# Generated by FakeRAM 2.0
VERSION 5.7 ;
BUSBITCHARS "[]" ;
PROPERTYDEFINITIONS
  MACRO width INTEGER ;
  MACRO depth INTEGER ;
  MACRO banks INTEGER ;
END PROPERTYDEFINITIONS
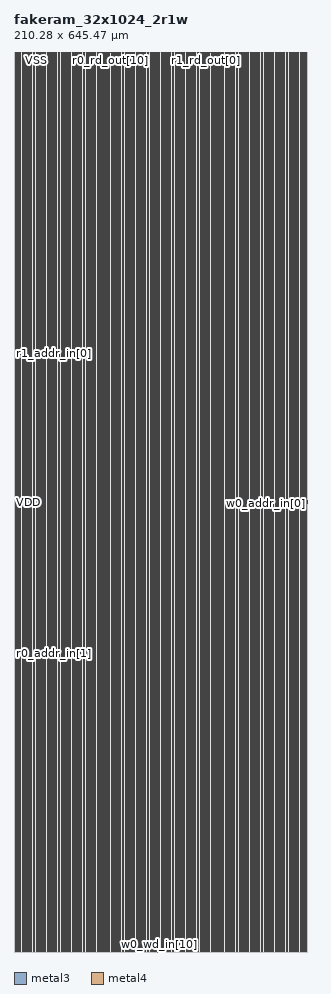
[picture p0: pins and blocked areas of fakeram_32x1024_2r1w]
MACRO fakeram_32x1024_2r1w
  PROPERTY width 32 ;
  PROPERTY depth 1024 ;
  PROPERTY banks 1 ;
  FOREIGN fakeram_32x1024_2r1w 0 0 ;
  SYMMETRY X Y R90 ;
  SIZE 210.280 BY 645.470 ;
  CLASS BLOCK ;
  PIN r0_addr_in[0]
    DIRECTION INPUT ;
    USE SIGNAL ;
    SHAPE ABUTMENT ;
    PORT
      LAYER metal3 ;
      RECT 0.000 214.200 0.070 214.270 ;
    END
  END r0_addr_in[0]
  PIN r0_addr_in[1]
    DIRECTION INPUT ;
    USE SIGNAL ;
    SHAPE ABUTMENT ;
    PORT
      LAYER metal3 ;
      RECT 0.000 214.340 0.070 214.410 ;
    END
  END r0_addr_in[1]
  PIN r0_addr_in[2]
    DIRECTION INPUT ;
    USE SIGNAL ;
    SHAPE ABUTMENT ;
    PORT
      LAYER metal3 ;
      RECT 0.000 214.480 0.070 214.550 ;
    END
  END r0_addr_in[2]
  PIN r0_addr_in[3]
    DIRECTION INPUT ;
    USE SIGNAL ;
    SHAPE ABUTMENT ;
    PORT
      LAYER metal3 ;
      RECT 0.000 214.620 0.070 214.690 ;
    END
  END r0_addr_in[3]
  PIN r0_addr_in[4]
    DIRECTION INPUT ;
    USE SIGNAL ;
    SHAPE ABUTMENT ;
    PORT
      LAYER metal3 ;
      RECT 0.000 214.760 0.070 214.830 ;
    END
  END r0_addr_in[4]
  PIN r0_addr_in[5]
    DIRECTION INPUT ;
    USE SIGNAL ;
    SHAPE ABUTMENT ;
    PORT
      LAYER metal3 ;
      RECT 0.000 214.900 0.070 214.970 ;
    END
  END r0_addr_in[5]
  PIN r0_addr_in[6]
    DIRECTION INPUT ;
    USE SIGNAL ;
    SHAPE ABUTMENT ;
    PORT
      LAYER metal3 ;
      RECT 0.000 215.040 0.070 215.110 ;
    END
  END r0_addr_in[6]
  PIN r0_addr_in[7]
    DIRECTION INPUT ;
    USE SIGNAL ;
    SHAPE ABUTMENT ;
    PORT
      LAYER metal3 ;
      RECT 0.000 215.180 0.070 215.250 ;
    END
  END r0_addr_in[7]
  PIN r0_addr_in[8]
    DIRECTION INPUT ;
    USE SIGNAL ;
    SHAPE ABUTMENT ;
    PORT
      LAYER metal3 ;
      RECT 0.000 215.320 0.070 215.390 ;
    END
  END r0_addr_in[8]
  PIN r0_addr_in[9]
    DIRECTION INPUT ;
    USE SIGNAL ;
    SHAPE ABUTMENT ;
    PORT
      LAYER metal3 ;
      RECT 0.000 215.460 0.070 215.530 ;
    END
  END r0_addr_in[9]
  PIN r0_ce_in
    DIRECTION INPUT ;
    USE SIGNAL ;
    SHAPE ABUTMENT ;
    PORT
      LAYER metal3 ;
      RECT 0.000 215.740 0.070 215.810 ;
    END
  END r0_ce_in
  PIN r0_clk
    DIRECTION INPUT ;
    USE SIGNAL ;
    SHAPE ABUTMENT ;
    PORT
      LAYER metal3 ;
      RECT 0.000 215.880 0.070 215.950 ;
    END
  END r0_clk
  PIN r0_rd_out[0]
    DIRECTION OUTPUT ;
    USE SIGNAL ;
    SHAPE ABUTMENT ;
    PORT
      LAYER metal3 ;
      RECT 67.725 645.400 67.795 645.470 ;
    END
  END r0_rd_out[0]
  PIN r0_rd_out[1]
    DIRECTION OUTPUT ;
    USE SIGNAL ;
    SHAPE ABUTMENT ;
    PORT
      LAYER metal3 ;
      RECT 67.865 645.400 67.935 645.470 ;
    END
  END r0_rd_out[1]
  PIN r0_rd_out[2]
    DIRECTION OUTPUT ;
    USE SIGNAL ;
    SHAPE ABUTMENT ;
    PORT
      LAYER metal3 ;
      RECT 68.005 645.400 68.075 645.470 ;
    END
  END r0_rd_out[2]
  PIN r0_rd_out[3]
    DIRECTION OUTPUT ;
    USE SIGNAL ;
    SHAPE ABUTMENT ;
    PORT
      LAYER metal3 ;
      RECT 68.145 645.400 68.215 645.470 ;
    END
  END r0_rd_out[3]
  PIN r0_rd_out[4]
    DIRECTION OUTPUT ;
    USE SIGNAL ;
    SHAPE ABUTMENT ;
    PORT
      LAYER metal3 ;
      RECT 68.285 645.400 68.355 645.470 ;
    END
  END r0_rd_out[4]
  PIN r0_rd_out[5]
    DIRECTION OUTPUT ;
    USE SIGNAL ;
    SHAPE ABUTMENT ;
    PORT
      LAYER metal3 ;
      RECT 68.425 645.400 68.495 645.470 ;
    END
  END r0_rd_out[5]
  PIN r0_rd_out[6]
    DIRECTION OUTPUT ;
    USE SIGNAL ;
    SHAPE ABUTMENT ;
    PORT
      LAYER metal3 ;
      RECT 68.565 645.400 68.635 645.470 ;
    END
  END r0_rd_out[6]
  PIN r0_rd_out[7]
    DIRECTION OUTPUT ;
    USE SIGNAL ;
    SHAPE ABUTMENT ;
    PORT
      LAYER metal3 ;
      RECT 68.705 645.400 68.775 645.470 ;
    END
  END r0_rd_out[7]
  PIN r0_rd_out[8]
    DIRECTION OUTPUT ;
    USE SIGNAL ;
    SHAPE ABUTMENT ;
    PORT
      LAYER metal3 ;
      RECT 68.845 645.400 68.915 645.470 ;
    END
  END r0_rd_out[8]
  PIN r0_rd_out[9]
    DIRECTION OUTPUT ;
    USE SIGNAL ;
    SHAPE ABUTMENT ;
    PORT
      LAYER metal3 ;
      RECT 68.985 645.400 69.055 645.470 ;
    END
  END r0_rd_out[9]
  PIN r0_rd_out[10]
    DIRECTION OUTPUT ;
    USE SIGNAL ;
    SHAPE ABUTMENT ;
    PORT
      LAYER metal3 ;
      RECT 69.125 645.400 69.195 645.470 ;
    END
  END r0_rd_out[10]
  PIN r0_rd_out[11]
    DIRECTION OUTPUT ;
    USE SIGNAL ;
    SHAPE ABUTMENT ;
    PORT
      LAYER metal3 ;
      RECT 69.265 645.400 69.335 645.470 ;
    END
  END r0_rd_out[11]
  PIN r0_rd_out[12]
    DIRECTION OUTPUT ;
    USE SIGNAL ;
    SHAPE ABUTMENT ;
    PORT
      LAYER metal3 ;
      RECT 69.405 645.400 69.475 645.470 ;
    END
  END r0_rd_out[12]
  PIN r0_rd_out[13]
    DIRECTION OUTPUT ;
    USE SIGNAL ;
    SHAPE ABUTMENT ;
    PORT
      LAYER metal3 ;
      RECT 69.545 645.400 69.615 645.470 ;
    END
  END r0_rd_out[13]
  PIN r0_rd_out[14]
    DIRECTION OUTPUT ;
    USE SIGNAL ;
    SHAPE ABUTMENT ;
    PORT
      LAYER metal3 ;
      RECT 69.685 645.400 69.755 645.470 ;
    END
  END r0_rd_out[14]
  PIN r0_rd_out[15]
    DIRECTION OUTPUT ;
    USE SIGNAL ;
    SHAPE ABUTMENT ;
    PORT
      LAYER metal3 ;
      RECT 69.825 645.400 69.895 645.470 ;
    END
  END r0_rd_out[15]
  PIN r0_rd_out[16]
    DIRECTION OUTPUT ;
    USE SIGNAL ;
    SHAPE ABUTMENT ;
    PORT
      LAYER metal3 ;
      RECT 69.965 645.400 70.035 645.470 ;
    END
  END r0_rd_out[16]
  PIN r0_rd_out[17]
    DIRECTION OUTPUT ;
    USE SIGNAL ;
    SHAPE ABUTMENT ;
    PORT
      LAYER metal3 ;
      RECT 70.105 645.400 70.175 645.470 ;
    END
  END r0_rd_out[17]
  PIN r0_rd_out[18]
    DIRECTION OUTPUT ;
    USE SIGNAL ;
    SHAPE ABUTMENT ;
    PORT
      LAYER metal3 ;
      RECT 70.245 645.400 70.315 645.470 ;
    END
  END r0_rd_out[18]
  PIN r0_rd_out[19]
    DIRECTION OUTPUT ;
    USE SIGNAL ;
    SHAPE ABUTMENT ;
    PORT
      LAYER metal3 ;
      RECT 70.385 645.400 70.455 645.470 ;
    END
  END r0_rd_out[19]
  PIN r0_rd_out[20]
    DIRECTION OUTPUT ;
    USE SIGNAL ;
    SHAPE ABUTMENT ;
    PORT
      LAYER metal3 ;
      RECT 70.525 645.400 70.595 645.470 ;
    END
  END r0_rd_out[20]
  PIN r0_rd_out[21]
    DIRECTION OUTPUT ;
    USE SIGNAL ;
    SHAPE ABUTMENT ;
    PORT
      LAYER metal3 ;
      RECT 70.665 645.400 70.735 645.470 ;
    END
  END r0_rd_out[21]
  PIN r0_rd_out[22]
    DIRECTION OUTPUT ;
    USE SIGNAL ;
    SHAPE ABUTMENT ;
    PORT
      LAYER metal3 ;
      RECT 70.805 645.400 70.875 645.470 ;
    END
  END r0_rd_out[22]
  PIN r0_rd_out[23]
    DIRECTION OUTPUT ;
    USE SIGNAL ;
    SHAPE ABUTMENT ;
    PORT
      LAYER metal3 ;
      RECT 70.945 645.400 71.015 645.470 ;
    END
  END r0_rd_out[23]
  PIN r0_rd_out[24]
    DIRECTION OUTPUT ;
    USE SIGNAL ;
    SHAPE ABUTMENT ;
    PORT
      LAYER metal3 ;
      RECT 71.085 645.400 71.155 645.470 ;
    END
  END r0_rd_out[24]
  PIN r0_rd_out[25]
    DIRECTION OUTPUT ;
    USE SIGNAL ;
    SHAPE ABUTMENT ;
    PORT
      LAYER metal3 ;
      RECT 71.225 645.400 71.295 645.470 ;
    END
  END r0_rd_out[25]
  PIN r0_rd_out[26]
    DIRECTION OUTPUT ;
    USE SIGNAL ;
    SHAPE ABUTMENT ;
    PORT
      LAYER metal3 ;
      RECT 71.365 645.400 71.435 645.470 ;
    END
  END r0_rd_out[26]
  PIN r0_rd_out[27]
    DIRECTION OUTPUT ;
    USE SIGNAL ;
    SHAPE ABUTMENT ;
    PORT
      LAYER metal3 ;
      RECT 71.505 645.400 71.575 645.470 ;
    END
  END r0_rd_out[27]
  PIN r0_rd_out[28]
    DIRECTION OUTPUT ;
    USE SIGNAL ;
    SHAPE ABUTMENT ;
    PORT
      LAYER metal3 ;
      RECT 71.645 645.400 71.715 645.470 ;
    END
  END r0_rd_out[28]
  PIN r0_rd_out[29]
    DIRECTION OUTPUT ;
    USE SIGNAL ;
    SHAPE ABUTMENT ;
    PORT
      LAYER metal3 ;
      RECT 71.785 645.400 71.855 645.470 ;
    END
  END r0_rd_out[29]
  PIN r0_rd_out[30]
    DIRECTION OUTPUT ;
    USE SIGNAL ;
    SHAPE ABUTMENT ;
    PORT
      LAYER metal3 ;
      RECT 71.925 645.400 71.995 645.470 ;
    END
  END r0_rd_out[30]
  PIN r0_rd_out[31]
    DIRECTION OUTPUT ;
    USE SIGNAL ;
    SHAPE ABUTMENT ;
    PORT
      LAYER metal3 ;
      RECT 72.065 645.400 72.135 645.470 ;
    END
  END r0_rd_out[31]
  PIN r1_addr_in[0]
    DIRECTION INPUT ;
    USE SIGNAL ;
    SHAPE ABUTMENT ;
    PORT
      LAYER metal3 ;
      RECT 0.000 429.240 0.070 429.310 ;
    END
  END r1_addr_in[0]
  PIN r1_addr_in[1]
    DIRECTION INPUT ;
    USE SIGNAL ;
    SHAPE ABUTMENT ;
    PORT
      LAYER metal3 ;
      RECT 0.000 429.380 0.070 429.450 ;
    END
  END r1_addr_in[1]
  PIN r1_addr_in[2]
    DIRECTION INPUT ;
    USE SIGNAL ;
    SHAPE ABUTMENT ;
    PORT
      LAYER metal3 ;
      RECT 0.000 429.520 0.070 429.590 ;
    END
  END r1_addr_in[2]
  PIN r1_addr_in[3]
    DIRECTION INPUT ;
    USE SIGNAL ;
    SHAPE ABUTMENT ;
    PORT
      LAYER metal3 ;
      RECT 0.000 429.660 0.070 429.730 ;
    END
  END r1_addr_in[3]
  PIN r1_addr_in[4]
    DIRECTION INPUT ;
    USE SIGNAL ;
    SHAPE ABUTMENT ;
    PORT
      LAYER metal3 ;
      RECT 0.000 429.800 0.070 429.870 ;
    END
  END r1_addr_in[4]
  PIN r1_addr_in[5]
    DIRECTION INPUT ;
    USE SIGNAL ;
    SHAPE ABUTMENT ;
    PORT
      LAYER metal3 ;
      RECT 0.000 429.940 0.070 430.010 ;
    END
  END r1_addr_in[5]
  PIN r1_addr_in[6]
    DIRECTION INPUT ;
    USE SIGNAL ;
    SHAPE ABUTMENT ;
    PORT
      LAYER metal3 ;
      RECT 0.000 430.080 0.070 430.150 ;
    END
  END r1_addr_in[6]
  PIN r1_addr_in[7]
    DIRECTION INPUT ;
    USE SIGNAL ;
    SHAPE ABUTMENT ;
    PORT
      LAYER metal3 ;
      RECT 0.000 430.220 0.070 430.290 ;
    END
  END r1_addr_in[7]
  PIN r1_addr_in[8]
    DIRECTION INPUT ;
    USE SIGNAL ;
    SHAPE ABUTMENT ;
    PORT
      LAYER metal3 ;
      RECT 0.000 430.360 0.070 430.430 ;
    END
  END r1_addr_in[8]
  PIN r1_addr_in[9]
    DIRECTION INPUT ;
    USE SIGNAL ;
    SHAPE ABUTMENT ;
    PORT
      LAYER metal3 ;
      RECT 0.000 430.500 0.070 430.570 ;
    END
  END r1_addr_in[9]
  PIN r1_ce_in
    DIRECTION INPUT ;
    USE SIGNAL ;
    SHAPE ABUTMENT ;
    PORT
      LAYER metal3 ;
      RECT 0.000 430.780 0.070 430.850 ;
    END
  END r1_ce_in
  PIN r1_clk
    DIRECTION INPUT ;
    USE SIGNAL ;
    SHAPE ABUTMENT ;
    PORT
      LAYER metal3 ;
      RECT 0.000 430.920 0.070 430.990 ;
    END
  END r1_clk
  PIN r1_rd_out[0]
    DIRECTION OUTPUT ;
    USE SIGNAL ;
    SHAPE ABUTMENT ;
    PORT
      LAYER metal3 ;
      RECT 137.725 645.400 137.795 645.470 ;
    END
  END r1_rd_out[0]
  PIN r1_rd_out[1]
    DIRECTION OUTPUT ;
    USE SIGNAL ;
    SHAPE ABUTMENT ;
    PORT
      LAYER metal3 ;
      RECT 137.865 645.400 137.935 645.470 ;
    END
  END r1_rd_out[1]
  PIN r1_rd_out[2]
    DIRECTION OUTPUT ;
    USE SIGNAL ;
    SHAPE ABUTMENT ;
    PORT
      LAYER metal3 ;
      RECT 138.005 645.400 138.075 645.470 ;
    END
  END r1_rd_out[2]
  PIN r1_rd_out[3]
    DIRECTION OUTPUT ;
    USE SIGNAL ;
    SHAPE ABUTMENT ;
    PORT
      LAYER metal3 ;
      RECT 138.145 645.400 138.215 645.470 ;
    END
  END r1_rd_out[3]
  PIN r1_rd_out[4]
    DIRECTION OUTPUT ;
    USE SIGNAL ;
    SHAPE ABUTMENT ;
    PORT
      LAYER metal3 ;
      RECT 138.285 645.400 138.355 645.470 ;
    END
  END r1_rd_out[4]
  PIN r1_rd_out[5]
    DIRECTION OUTPUT ;
    USE SIGNAL ;
    SHAPE ABUTMENT ;
    PORT
      LAYER metal3 ;
      RECT 138.425 645.400 138.495 645.470 ;
    END
  END r1_rd_out[5]
  PIN r1_rd_out[6]
    DIRECTION OUTPUT ;
    USE SIGNAL ;
    SHAPE ABUTMENT ;
    PORT
      LAYER metal3 ;
      RECT 138.565 645.400 138.635 645.470 ;
    END
  END r1_rd_out[6]
  PIN r1_rd_out[7]
    DIRECTION OUTPUT ;
    USE SIGNAL ;
    SHAPE ABUTMENT ;
    PORT
      LAYER metal3 ;
      RECT 138.705 645.400 138.775 645.470 ;
    END
  END r1_rd_out[7]
  PIN r1_rd_out[8]
    DIRECTION OUTPUT ;
    USE SIGNAL ;
    SHAPE ABUTMENT ;
    PORT
      LAYER metal3 ;
      RECT 138.845 645.400 138.915 645.470 ;
    END
  END r1_rd_out[8]
  PIN r1_rd_out[9]
    DIRECTION OUTPUT ;
    USE SIGNAL ;
    SHAPE ABUTMENT ;
    PORT
      LAYER metal3 ;
      RECT 138.985 645.400 139.055 645.470 ;
    END
  END r1_rd_out[9]
  PIN r1_rd_out[10]
    DIRECTION OUTPUT ;
    USE SIGNAL ;
    SHAPE ABUTMENT ;
    PORT
      LAYER metal3 ;
      RECT 139.125 645.400 139.195 645.470 ;
    END
  END r1_rd_out[10]
  PIN r1_rd_out[11]
    DIRECTION OUTPUT ;
    USE SIGNAL ;
    SHAPE ABUTMENT ;
    PORT
      LAYER metal3 ;
      RECT 139.265 645.400 139.335 645.470 ;
    END
  END r1_rd_out[11]
  PIN r1_rd_out[12]
    DIRECTION OUTPUT ;
    USE SIGNAL ;
    SHAPE ABUTMENT ;
    PORT
      LAYER metal3 ;
      RECT 139.405 645.400 139.475 645.470 ;
    END
  END r1_rd_out[12]
  PIN r1_rd_out[13]
    DIRECTION OUTPUT ;
    USE SIGNAL ;
    SHAPE ABUTMENT ;
    PORT
      LAYER metal3 ;
      RECT 139.545 645.400 139.615 645.470 ;
    END
  END r1_rd_out[13]
  PIN r1_rd_out[14]
    DIRECTION OUTPUT ;
    USE SIGNAL ;
    SHAPE ABUTMENT ;
    PORT
      LAYER metal3 ;
      RECT 139.685 645.400 139.755 645.470 ;
    END
  END r1_rd_out[14]
  PIN r1_rd_out[15]
    DIRECTION OUTPUT ;
    USE SIGNAL ;
    SHAPE ABUTMENT ;
    PORT
      LAYER metal3 ;
      RECT 139.825 645.400 139.895 645.470 ;
    END
  END r1_rd_out[15]
  PIN r1_rd_out[16]
    DIRECTION OUTPUT ;
    USE SIGNAL ;
    SHAPE ABUTMENT ;
    PORT
      LAYER metal3 ;
      RECT 139.965 645.400 140.035 645.470 ;
    END
  END r1_rd_out[16]
  PIN r1_rd_out[17]
    DIRECTION OUTPUT ;
    USE SIGNAL ;
    SHAPE ABUTMENT ;
    PORT
      LAYER metal3 ;
      RECT 140.105 645.400 140.175 645.470 ;
    END
  END r1_rd_out[17]
  PIN r1_rd_out[18]
    DIRECTION OUTPUT ;
    USE SIGNAL ;
    SHAPE ABUTMENT ;
    PORT
      LAYER metal3 ;
      RECT 140.245 645.400 140.315 645.470 ;
    END
  END r1_rd_out[18]
  PIN r1_rd_out[19]
    DIRECTION OUTPUT ;
    USE SIGNAL ;
    SHAPE ABUTMENT ;
    PORT
      LAYER metal3 ;
      RECT 140.385 645.400 140.455 645.470 ;
    END
  END r1_rd_out[19]
  PIN r1_rd_out[20]
    DIRECTION OUTPUT ;
    USE SIGNAL ;
    SHAPE ABUTMENT ;
    PORT
      LAYER metal3 ;
      RECT 140.525 645.400 140.595 645.470 ;
    END
  END r1_rd_out[20]
  PIN r1_rd_out[21]
    DIRECTION OUTPUT ;
    USE SIGNAL ;
    SHAPE ABUTMENT ;
    PORT
      LAYER metal3 ;
      RECT 140.665 645.400 140.735 645.470 ;
    END
  END r1_rd_out[21]
  PIN r1_rd_out[22]
    DIRECTION OUTPUT ;
    USE SIGNAL ;
    SHAPE ABUTMENT ;
    PORT
      LAYER metal3 ;
      RECT 140.805 645.400 140.875 645.470 ;
    END
  END r1_rd_out[22]
  PIN r1_rd_out[23]
    DIRECTION OUTPUT ;
    USE SIGNAL ;
    SHAPE ABUTMENT ;
    PORT
      LAYER metal3 ;
      RECT 140.945 645.400 141.015 645.470 ;
    END
  END r1_rd_out[23]
  PIN r1_rd_out[24]
    DIRECTION OUTPUT ;
    USE SIGNAL ;
    SHAPE ABUTMENT ;
    PORT
      LAYER metal3 ;
      RECT 141.085 645.400 141.155 645.470 ;
    END
  END r1_rd_out[24]
  PIN r1_rd_out[25]
    DIRECTION OUTPUT ;
    USE SIGNAL ;
    SHAPE ABUTMENT ;
    PORT
      LAYER metal3 ;
      RECT 141.225 645.400 141.295 645.470 ;
    END
  END r1_rd_out[25]
  PIN r1_rd_out[26]
    DIRECTION OUTPUT ;
    USE SIGNAL ;
    SHAPE ABUTMENT ;
    PORT
      LAYER metal3 ;
      RECT 141.365 645.400 141.435 645.470 ;
    END
  END r1_rd_out[26]
  PIN r1_rd_out[27]
    DIRECTION OUTPUT ;
    USE SIGNAL ;
    SHAPE ABUTMENT ;
    PORT
      LAYER metal3 ;
      RECT 141.505 645.400 141.575 645.470 ;
    END
  END r1_rd_out[27]
  PIN r1_rd_out[28]
    DIRECTION OUTPUT ;
    USE SIGNAL ;
    SHAPE ABUTMENT ;
    PORT
      LAYER metal3 ;
      RECT 141.645 645.400 141.715 645.470 ;
    END
  END r1_rd_out[28]
  PIN r1_rd_out[29]
    DIRECTION OUTPUT ;
    USE SIGNAL ;
    SHAPE ABUTMENT ;
    PORT
      LAYER metal3 ;
      RECT 141.785 645.400 141.855 645.470 ;
    END
  END r1_rd_out[29]
  PIN r1_rd_out[30]
    DIRECTION OUTPUT ;
    USE SIGNAL ;
    SHAPE ABUTMENT ;
    PORT
      LAYER metal3 ;
      RECT 141.925 645.400 141.995 645.470 ;
    END
  END r1_rd_out[30]
  PIN r1_rd_out[31]
    DIRECTION OUTPUT ;
    USE SIGNAL ;
    SHAPE ABUTMENT ;
    PORT
      LAYER metal3 ;
      RECT 142.065 645.400 142.135 645.470 ;
    END
  END r1_rd_out[31]
  PIN w0_addr_in[0]
    DIRECTION INPUT ;
    USE SIGNAL ;
    SHAPE ABUTMENT ;
    PORT
      LAYER metal3 ;
      RECT 210.210 321.720 210.280 321.790 ;
    END
  END w0_addr_in[0]
  PIN w0_addr_in[1]
    DIRECTION INPUT ;
    USE SIGNAL ;
    SHAPE ABUTMENT ;
    PORT
      LAYER metal3 ;
      RECT 210.210 321.860 210.280 321.930 ;
    END
  END w0_addr_in[1]
  PIN w0_addr_in[2]
    DIRECTION INPUT ;
    USE SIGNAL ;
    SHAPE ABUTMENT ;
    PORT
      LAYER metal3 ;
      RECT 210.210 322.000 210.280 322.070 ;
    END
  END w0_addr_in[2]
  PIN w0_addr_in[3]
    DIRECTION INPUT ;
    USE SIGNAL ;
    SHAPE ABUTMENT ;
    PORT
      LAYER metal3 ;
      RECT 210.210 322.140 210.280 322.210 ;
    END
  END w0_addr_in[3]
  PIN w0_addr_in[4]
    DIRECTION INPUT ;
    USE SIGNAL ;
    SHAPE ABUTMENT ;
    PORT
      LAYER metal3 ;
      RECT 210.210 322.280 210.280 322.350 ;
    END
  END w0_addr_in[4]
  PIN w0_addr_in[5]
    DIRECTION INPUT ;
    USE SIGNAL ;
    SHAPE ABUTMENT ;
    PORT
      LAYER metal3 ;
      RECT 210.210 322.420 210.280 322.490 ;
    END
  END w0_addr_in[5]
  PIN w0_addr_in[6]
    DIRECTION INPUT ;
    USE SIGNAL ;
    SHAPE ABUTMENT ;
    PORT
      LAYER metal3 ;
      RECT 210.210 322.560 210.280 322.630 ;
    END
  END w0_addr_in[6]
  PIN w0_addr_in[7]
    DIRECTION INPUT ;
    USE SIGNAL ;
    SHAPE ABUTMENT ;
    PORT
      LAYER metal3 ;
      RECT 210.210 322.700 210.280 322.770 ;
    END
  END w0_addr_in[7]
  PIN w0_addr_in[8]
    DIRECTION INPUT ;
    USE SIGNAL ;
    SHAPE ABUTMENT ;
    PORT
      LAYER metal3 ;
      RECT 210.210 322.840 210.280 322.910 ;
    END
  END w0_addr_in[8]
  PIN w0_addr_in[9]
    DIRECTION INPUT ;
    USE SIGNAL ;
    SHAPE ABUTMENT ;
    PORT
      LAYER metal3 ;
      RECT 210.210 322.980 210.280 323.050 ;
    END
  END w0_addr_in[9]
  PIN w0_we_in
    DIRECTION INPUT ;
    USE SIGNAL ;
    SHAPE ABUTMENT ;
    PORT
      LAYER metal3 ;
      RECT 210.210 323.260 210.280 323.330 ;
    END
  END w0_we_in
  PIN w0_ce_in
    DIRECTION INPUT ;
    USE SIGNAL ;
    SHAPE ABUTMENT ;
    PORT
      LAYER metal3 ;
      RECT 210.210 323.400 210.280 323.470 ;
    END
  END w0_ce_in
  PIN w0_clk
    DIRECTION INPUT ;
    USE SIGNAL ;
    SHAPE ABUTMENT ;
    PORT
      LAYER metal3 ;
      RECT 210.210 323.540 210.280 323.610 ;
    END
  END w0_clk
  PIN w0_wd_in[0]
    DIRECTION INPUT ;
    USE SIGNAL ;
    SHAPE ABUTMENT ;
    PORT
      LAYER metal3 ;
      RECT 102.725 0.000 102.795 0.070 ;
    END
  END w0_wd_in[0]
  PIN w0_wd_in[1]
    DIRECTION INPUT ;
    USE SIGNAL ;
    SHAPE ABUTMENT ;
    PORT
      LAYER metal3 ;
      RECT 102.865 0.000 102.935 0.070 ;
    END
  END w0_wd_in[1]
  PIN w0_wd_in[2]
    DIRECTION INPUT ;
    USE SIGNAL ;
    SHAPE ABUTMENT ;
    PORT
      LAYER metal3 ;
      RECT 103.005 0.000 103.075 0.070 ;
    END
  END w0_wd_in[2]
  PIN w0_wd_in[3]
    DIRECTION INPUT ;
    USE SIGNAL ;
    SHAPE ABUTMENT ;
    PORT
      LAYER metal3 ;
      RECT 103.145 0.000 103.215 0.070 ;
    END
  END w0_wd_in[3]
  PIN w0_wd_in[4]
    DIRECTION INPUT ;
    USE SIGNAL ;
    SHAPE ABUTMENT ;
    PORT
      LAYER metal3 ;
      RECT 103.285 0.000 103.355 0.070 ;
    END
  END w0_wd_in[4]
  PIN w0_wd_in[5]
    DIRECTION INPUT ;
    USE SIGNAL ;
    SHAPE ABUTMENT ;
    PORT
      LAYER metal3 ;
      RECT 103.425 0.000 103.495 0.070 ;
    END
  END w0_wd_in[5]
  PIN w0_wd_in[6]
    DIRECTION INPUT ;
    USE SIGNAL ;
    SHAPE ABUTMENT ;
    PORT
      LAYER metal3 ;
      RECT 103.565 0.000 103.635 0.070 ;
    END
  END w0_wd_in[6]
  PIN w0_wd_in[7]
    DIRECTION INPUT ;
    USE SIGNAL ;
    SHAPE ABUTMENT ;
    PORT
      LAYER metal3 ;
      RECT 103.705 0.000 103.775 0.070 ;
    END
  END w0_wd_in[7]
  PIN w0_wd_in[8]
    DIRECTION INPUT ;
    USE SIGNAL ;
    SHAPE ABUTMENT ;
    PORT
      LAYER metal3 ;
      RECT 103.845 0.000 103.915 0.070 ;
    END
  END w0_wd_in[8]
  PIN w0_wd_in[9]
    DIRECTION INPUT ;
    USE SIGNAL ;
    SHAPE ABUTMENT ;
    PORT
      LAYER metal3 ;
      RECT 103.985 0.000 104.055 0.070 ;
    END
  END w0_wd_in[9]
  PIN w0_wd_in[10]
    DIRECTION INPUT ;
    USE SIGNAL ;
    SHAPE ABUTMENT ;
    PORT
      LAYER metal3 ;
      RECT 104.125 0.000 104.195 0.070 ;
    END
  END w0_wd_in[10]
  PIN w0_wd_in[11]
    DIRECTION INPUT ;
    USE SIGNAL ;
    SHAPE ABUTMENT ;
    PORT
      LAYER metal3 ;
      RECT 104.265 0.000 104.335 0.070 ;
    END
  END w0_wd_in[11]
  PIN w0_wd_in[12]
    DIRECTION INPUT ;
    USE SIGNAL ;
    SHAPE ABUTMENT ;
    PORT
      LAYER metal3 ;
      RECT 104.405 0.000 104.475 0.070 ;
    END
  END w0_wd_in[12]
  PIN w0_wd_in[13]
    DIRECTION INPUT ;
    USE SIGNAL ;
    SHAPE ABUTMENT ;
    PORT
      LAYER metal3 ;
      RECT 104.545 0.000 104.615 0.070 ;
    END
  END w0_wd_in[13]
  PIN w0_wd_in[14]
    DIRECTION INPUT ;
    USE SIGNAL ;
    SHAPE ABUTMENT ;
    PORT
      LAYER metal3 ;
      RECT 104.685 0.000 104.755 0.070 ;
    END
  END w0_wd_in[14]
  PIN w0_wd_in[15]
    DIRECTION INPUT ;
    USE SIGNAL ;
    SHAPE ABUTMENT ;
    PORT
      LAYER metal3 ;
      RECT 104.825 0.000 104.895 0.070 ;
    END
  END w0_wd_in[15]
  PIN w0_wd_in[16]
    DIRECTION INPUT ;
    USE SIGNAL ;
    SHAPE ABUTMENT ;
    PORT
      LAYER metal3 ;
      RECT 104.965 0.000 105.035 0.070 ;
    END
  END w0_wd_in[16]
  PIN w0_wd_in[17]
    DIRECTION INPUT ;
    USE SIGNAL ;
    SHAPE ABUTMENT ;
    PORT
      LAYER metal3 ;
      RECT 105.105 0.000 105.175 0.070 ;
    END
  END w0_wd_in[17]
  PIN w0_wd_in[18]
    DIRECTION INPUT ;
    USE SIGNAL ;
    SHAPE ABUTMENT ;
    PORT
      LAYER metal3 ;
      RECT 105.245 0.000 105.315 0.070 ;
    END
  END w0_wd_in[18]
  PIN w0_wd_in[19]
    DIRECTION INPUT ;
    USE SIGNAL ;
    SHAPE ABUTMENT ;
    PORT
      LAYER metal3 ;
      RECT 105.385 0.000 105.455 0.070 ;
    END
  END w0_wd_in[19]
  PIN w0_wd_in[20]
    DIRECTION INPUT ;
    USE SIGNAL ;
    SHAPE ABUTMENT ;
    PORT
      LAYER metal3 ;
      RECT 105.525 0.000 105.595 0.070 ;
    END
  END w0_wd_in[20]
  PIN w0_wd_in[21]
    DIRECTION INPUT ;
    USE SIGNAL ;
    SHAPE ABUTMENT ;
    PORT
      LAYER metal3 ;
      RECT 105.665 0.000 105.735 0.070 ;
    END
  END w0_wd_in[21]
  PIN w0_wd_in[22]
    DIRECTION INPUT ;
    USE SIGNAL ;
    SHAPE ABUTMENT ;
    PORT
      LAYER metal3 ;
      RECT 105.805 0.000 105.875 0.070 ;
    END
  END w0_wd_in[22]
  PIN w0_wd_in[23]
    DIRECTION INPUT ;
    USE SIGNAL ;
    SHAPE ABUTMENT ;
    PORT
      LAYER metal3 ;
      RECT 105.945 0.000 106.015 0.070 ;
    END
  END w0_wd_in[23]
  PIN w0_wd_in[24]
    DIRECTION INPUT ;
    USE SIGNAL ;
    SHAPE ABUTMENT ;
    PORT
      LAYER metal3 ;
      RECT 106.085 0.000 106.155 0.070 ;
    END
  END w0_wd_in[24]
  PIN w0_wd_in[25]
    DIRECTION INPUT ;
    USE SIGNAL ;
    SHAPE ABUTMENT ;
    PORT
      LAYER metal3 ;
      RECT 106.225 0.000 106.295 0.070 ;
    END
  END w0_wd_in[25]
  PIN w0_wd_in[26]
    DIRECTION INPUT ;
    USE SIGNAL ;
    SHAPE ABUTMENT ;
    PORT
      LAYER metal3 ;
      RECT 106.365 0.000 106.435 0.070 ;
    END
  END w0_wd_in[26]
  PIN w0_wd_in[27]
    DIRECTION INPUT ;
    USE SIGNAL ;
    SHAPE ABUTMENT ;
    PORT
      LAYER metal3 ;
      RECT 106.505 0.000 106.575 0.070 ;
    END
  END w0_wd_in[27]
  PIN w0_wd_in[28]
    DIRECTION INPUT ;
    USE SIGNAL ;
    SHAPE ABUTMENT ;
    PORT
      LAYER metal3 ;
      RECT 106.645 0.000 106.715 0.070 ;
    END
  END w0_wd_in[28]
  PIN w0_wd_in[29]
    DIRECTION INPUT ;
    USE SIGNAL ;
    SHAPE ABUTMENT ;
    PORT
      LAYER metal3 ;
      RECT 106.785 0.000 106.855 0.070 ;
    END
  END w0_wd_in[29]
  PIN w0_wd_in[30]
    DIRECTION INPUT ;
    USE SIGNAL ;
    SHAPE ABUTMENT ;
    PORT
      LAYER metal3 ;
      RECT 106.925 0.000 106.995 0.070 ;
    END
  END w0_wd_in[30]
  PIN w0_wd_in[31]
    DIRECTION INPUT ;
    USE SIGNAL ;
    SHAPE ABUTMENT ;
    PORT
      LAYER metal3 ;
      RECT 107.065 0.000 107.135 0.070 ;
    END
  END w0_wd_in[31]
  PIN VSS
    DIRECTION INOUT ;
    USE GROUND ;
    PORT
      LAYER metal4 ;
      RECT 2.450 0.140 2.730 645.330 ;
      RECT 4.690 0.140 4.970 645.330 ;
      RECT 6.930 0.140 7.210 645.330 ;
      RECT 9.170 0.140 9.450 645.330 ;
      RECT 11.410 0.140 11.690 645.330 ;
      RECT 13.650 0.140 13.930 645.330 ;
      RECT 15.890 0.140 16.170 645.330 ;
      RECT 18.130 0.140 18.410 645.330 ;
      RECT 20.370 0.140 20.650 645.330 ;
      RECT 22.610 0.140 22.890 645.330 ;
      RECT 24.850 0.140 25.130 645.330 ;
      RECT 27.090 0.140 27.370 645.330 ;
      RECT 29.330 0.140 29.610 645.330 ;
      RECT 31.570 0.140 31.850 645.330 ;
      RECT 33.810 0.140 34.090 645.330 ;
      RECT 36.050 0.140 36.330 645.330 ;
      RECT 38.290 0.140 38.570 645.330 ;
      RECT 40.530 0.140 40.810 645.330 ;
      RECT 42.770 0.140 43.050 645.330 ;
      RECT 45.010 0.140 45.290 645.330 ;
      RECT 47.250 0.140 47.530 645.330 ;
      RECT 49.490 0.140 49.770 645.330 ;
      RECT 51.730 0.140 52.010 645.330 ;
      RECT 53.970 0.140 54.250 645.330 ;
      RECT 56.210 0.140 56.490 645.330 ;
      RECT 58.450 0.140 58.730 645.330 ;
      RECT 60.690 0.140 60.970 645.330 ;
      RECT 62.930 0.140 63.210 645.330 ;
      RECT 65.170 0.140 65.450 645.330 ;
      RECT 67.410 0.140 67.690 645.330 ;
      RECT 69.650 0.140 69.930 645.330 ;
      RECT 71.890 0.140 72.170 645.330 ;
      RECT 74.130 0.140 74.410 645.330 ;
      RECT 76.370 0.140 76.650 645.330 ;
      RECT 78.610 0.140 78.890 645.330 ;
      RECT 80.850 0.140 81.130 645.330 ;
      RECT 83.090 0.140 83.370 645.330 ;
      RECT 85.330 0.140 85.610 645.330 ;
      RECT 87.570 0.140 87.850 645.330 ;
      RECT 89.810 0.140 90.090 645.330 ;
      RECT 92.050 0.140 92.330 645.330 ;
      RECT 94.290 0.140 94.570 645.330 ;
      RECT 96.530 0.140 96.810 645.330 ;
      RECT 98.770 0.140 99.050 645.330 ;
      RECT 101.010 0.140 101.290 645.330 ;
      RECT 103.250 0.140 103.530 645.330 ;
      RECT 105.490 0.140 105.770 645.330 ;
      RECT 107.730 0.140 108.010 645.330 ;
      RECT 109.970 0.140 110.250 645.330 ;
      RECT 112.210 0.140 112.490 645.330 ;
      RECT 114.450 0.140 114.730 645.330 ;
      RECT 116.690 0.140 116.970 645.330 ;
      RECT 118.930 0.140 119.210 645.330 ;
      RECT 121.170 0.140 121.450 645.330 ;
      RECT 123.410 0.140 123.690 645.330 ;
      RECT 125.650 0.140 125.930 645.330 ;
      RECT 127.890 0.140 128.170 645.330 ;
      RECT 130.130 0.140 130.410 645.330 ;
      RECT 132.370 0.140 132.650 645.330 ;
      RECT 134.610 0.140 134.890 645.330 ;
      RECT 136.850 0.140 137.130 645.330 ;
      RECT 139.090 0.140 139.370 645.330 ;
      RECT 141.330 0.140 141.610 645.330 ;
      RECT 143.570 0.140 143.850 645.330 ;
      RECT 145.810 0.140 146.090 645.330 ;
      RECT 148.050 0.140 148.330 645.330 ;
      RECT 150.290 0.140 150.570 645.330 ;
      RECT 152.530 0.140 152.810 645.330 ;
      RECT 154.770 0.140 155.050 645.330 ;
      RECT 157.010 0.140 157.290 645.330 ;
      RECT 159.250 0.140 159.530 645.330 ;
      RECT 161.490 0.140 161.770 645.330 ;
      RECT 163.730 0.140 164.010 645.330 ;
      RECT 165.970 0.140 166.250 645.330 ;
      RECT 168.210 0.140 168.490 645.330 ;
      RECT 170.450 0.140 170.730 645.330 ;
      RECT 172.690 0.140 172.970 645.330 ;
      RECT 174.930 0.140 175.210 645.330 ;
      RECT 177.170 0.140 177.450 645.330 ;
      RECT 179.410 0.140 179.690 645.330 ;
      RECT 181.650 0.140 181.930 645.330 ;
      RECT 183.890 0.140 184.170 645.330 ;
      RECT 186.130 0.140 186.410 645.330 ;
      RECT 188.370 0.140 188.650 645.330 ;
      RECT 190.610 0.140 190.890 645.330 ;
      RECT 192.850 0.140 193.130 645.330 ;
      RECT 195.090 0.140 195.370 645.330 ;
      RECT 197.330 0.140 197.610 645.330 ;
      RECT 199.570 0.140 199.850 645.330 ;
      RECT 201.810 0.140 202.090 645.330 ;
      RECT 204.050 0.140 204.330 645.330 ;
      RECT 206.290 0.140 206.570 645.330 ;
      RECT 208.530 0.140 208.810 645.330 ;
    END
  END VSS
  PIN VDD
    DIRECTION INOUT ;
    USE POWER ;
    PORT
      LAYER metal4 ;
      RECT 1.330 0.140 1.610 645.330 ;
      RECT 3.570 0.140 3.850 645.330 ;
      RECT 5.810 0.140 6.090 645.330 ;
      RECT 8.050 0.140 8.330 645.330 ;
      RECT 10.290 0.140 10.570 645.330 ;
      RECT 12.530 0.140 12.810 645.330 ;
      RECT 14.770 0.140 15.050 645.330 ;
      RECT 17.010 0.140 17.290 645.330 ;
      RECT 19.250 0.140 19.530 645.330 ;
      RECT 21.490 0.140 21.770 645.330 ;
      RECT 23.730 0.140 24.010 645.330 ;
      RECT 25.970 0.140 26.250 645.330 ;
      RECT 28.210 0.140 28.490 645.330 ;
      RECT 30.450 0.140 30.730 645.330 ;
      RECT 32.690 0.140 32.970 645.330 ;
      RECT 34.930 0.140 35.210 645.330 ;
      RECT 37.170 0.140 37.450 645.330 ;
      RECT 39.410 0.140 39.690 645.330 ;
      RECT 41.650 0.140 41.930 645.330 ;
      RECT 43.890 0.140 44.170 645.330 ;
      RECT 46.130 0.140 46.410 645.330 ;
      RECT 48.370 0.140 48.650 645.330 ;
      RECT 50.610 0.140 50.890 645.330 ;
      RECT 52.850 0.140 53.130 645.330 ;
      RECT 55.090 0.140 55.370 645.330 ;
      RECT 57.330 0.140 57.610 645.330 ;
      RECT 59.570 0.140 59.850 645.330 ;
      RECT 61.810 0.140 62.090 645.330 ;
      RECT 64.050 0.140 64.330 645.330 ;
      RECT 66.290 0.140 66.570 645.330 ;
      RECT 68.530 0.140 68.810 645.330 ;
      RECT 70.770 0.140 71.050 645.330 ;
      RECT 73.010 0.140 73.290 645.330 ;
      RECT 75.250 0.140 75.530 645.330 ;
      RECT 77.490 0.140 77.770 645.330 ;
      RECT 79.730 0.140 80.010 645.330 ;
      RECT 81.970 0.140 82.250 645.330 ;
      RECT 84.210 0.140 84.490 645.330 ;
      RECT 86.450 0.140 86.730 645.330 ;
      RECT 88.690 0.140 88.970 645.330 ;
      RECT 90.930 0.140 91.210 645.330 ;
      RECT 93.170 0.140 93.450 645.330 ;
      RECT 95.410 0.140 95.690 645.330 ;
      RECT 97.650 0.140 97.930 645.330 ;
      RECT 99.890 0.140 100.170 645.330 ;
      RECT 102.130 0.140 102.410 645.330 ;
      RECT 104.370 0.140 104.650 645.330 ;
      RECT 106.610 0.140 106.890 645.330 ;
      RECT 108.850 0.140 109.130 645.330 ;
      RECT 111.090 0.140 111.370 645.330 ;
      RECT 113.330 0.140 113.610 645.330 ;
      RECT 115.570 0.140 115.850 645.330 ;
      RECT 117.810 0.140 118.090 645.330 ;
      RECT 120.050 0.140 120.330 645.330 ;
      RECT 122.290 0.140 122.570 645.330 ;
      RECT 124.530 0.140 124.810 645.330 ;
      RECT 126.770 0.140 127.050 645.330 ;
      RECT 129.010 0.140 129.290 645.330 ;
      RECT 131.250 0.140 131.530 645.330 ;
      RECT 133.490 0.140 133.770 645.330 ;
      RECT 135.730 0.140 136.010 645.330 ;
      RECT 137.970 0.140 138.250 645.330 ;
      RECT 140.210 0.140 140.490 645.330 ;
      RECT 142.450 0.140 142.730 645.330 ;
      RECT 144.690 0.140 144.970 645.330 ;
      RECT 146.930 0.140 147.210 645.330 ;
      RECT 149.170 0.140 149.450 645.330 ;
      RECT 151.410 0.140 151.690 645.330 ;
      RECT 153.650 0.140 153.930 645.330 ;
      RECT 155.890 0.140 156.170 645.330 ;
      RECT 158.130 0.140 158.410 645.330 ;
      RECT 160.370 0.140 160.650 645.330 ;
      RECT 162.610 0.140 162.890 645.330 ;
      RECT 164.850 0.140 165.130 645.330 ;
      RECT 167.090 0.140 167.370 645.330 ;
      RECT 169.330 0.140 169.610 645.330 ;
      RECT 171.570 0.140 171.850 645.330 ;
      RECT 173.810 0.140 174.090 645.330 ;
      RECT 176.050 0.140 176.330 645.330 ;
      RECT 178.290 0.140 178.570 645.330 ;
      RECT 180.530 0.140 180.810 645.330 ;
      RECT 182.770 0.140 183.050 645.330 ;
      RECT 185.010 0.140 185.290 645.330 ;
      RECT 187.250 0.140 187.530 645.330 ;
      RECT 189.490 0.140 189.770 645.330 ;
      RECT 191.730 0.140 192.010 645.330 ;
      RECT 193.970 0.140 194.250 645.330 ;
      RECT 196.210 0.140 196.490 645.330 ;
      RECT 198.450 0.140 198.730 645.330 ;
      RECT 200.690 0.140 200.970 645.330 ;
      RECT 202.930 0.140 203.210 645.330 ;
      RECT 205.170 0.140 205.450 645.330 ;
      RECT 207.410 0.140 207.690 645.330 ;
      RECT 209.650 0.140 209.930 645.330 ;
    END
  END VDD
  OBS
    LAYER metal1 ;
    RECT 0 0 210.280 645.470 ;
    LAYER metal2 ;
    RECT 0 0 210.280 645.470 ;
    LAYER metal3 ;
    RECT 0 0 210.280 645.470 ;
    LAYER metal4 ;
    RECT 0 0 210.280 645.470 ;
    LAYER OVERLAP ;
    RECT 0 0 210.280 645.470 ;
  END
END fakeram_32x1024_2r1w

END LIBRARY
